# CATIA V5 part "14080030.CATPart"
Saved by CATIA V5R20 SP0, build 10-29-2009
Part number: 14080030
Definition: NONE
Nomenclature: 14080030
Source: Unknown
Description: 14080030
Bounding box of the stored display mesh (mm): x -15 to 60, y -54 to 43.912, z -44.1 to 44.1
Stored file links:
  C:\Users\Utente\Desktop\IO LAVORO\3D X SITO CF\X SITO\PLASTICA\RF2\14080030.CATPart

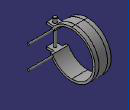
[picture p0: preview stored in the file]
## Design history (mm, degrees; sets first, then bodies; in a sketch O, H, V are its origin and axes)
Body1 "14080030" (main body)
  Solid1: solid without history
